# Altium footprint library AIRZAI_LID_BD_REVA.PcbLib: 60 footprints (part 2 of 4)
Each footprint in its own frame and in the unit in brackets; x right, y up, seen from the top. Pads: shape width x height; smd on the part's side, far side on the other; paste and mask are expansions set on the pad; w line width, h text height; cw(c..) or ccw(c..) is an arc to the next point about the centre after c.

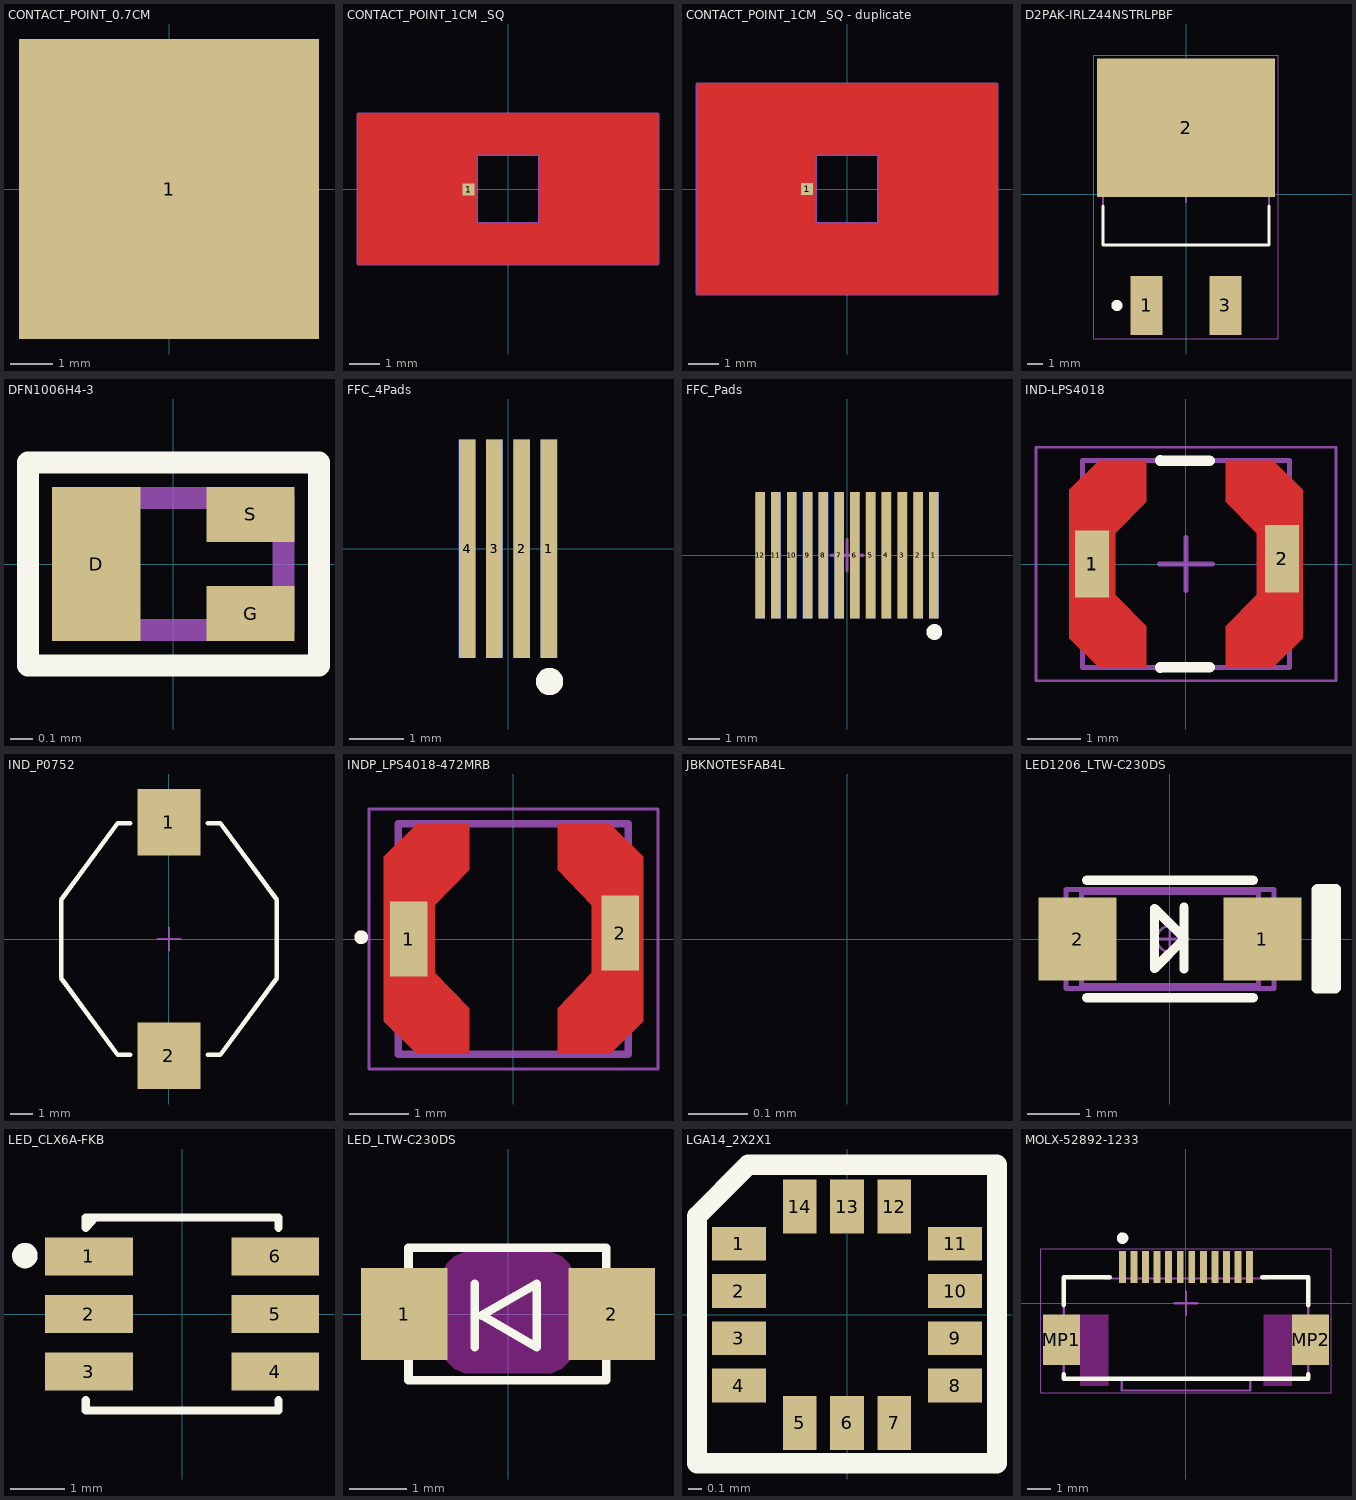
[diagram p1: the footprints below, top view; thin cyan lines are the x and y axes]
## CONTACT_POINT_0.7CM [mm]
pads (1):
  rect 7x7 smd paste-3.5 mask-3.5: 1(0,0)

## CONTACT_POINT_1CM _SQ [mm]
pads (1):
  rect 0.4x0.4 smd paste-2 mask-2: 1(-1.312,-0.018)
Top Layer:
  region: 2.48,-2.5 1.05,-1.15 -1.05,-1.15 -1.05,2.5 -5,2.5 -5,-2.5
  region: -2.48,2.5 -1.05,1.15 1.05,1.15 1.05,-2.5 5,-2.5 5,2.5
Mechanical 1:
  lines w0.1: -5,-2.5 -5,2.5 5,2.5 5,-2.5 -5,-2.5 ; -1.05,-1.15 1.05,-1.15 1.05,1.15 -1.05,1.15 -1.05,-1.15

## CONTACT_POINT_1CM _SQ - duplicate [mm]
pads (1):
  rect 0.4x0.4 smd paste-2 mask-2: 1(-1.325,0)
Top Layer:
  region: 5,-3.5 5,3.5 -3.4,3.5 -1.05,1.15 1.05,1.15 1.05,-3.498 1.052,-3.5
  region: -5,3.5 -5,-3.5 3.4,-3.5 1.05,-1.15 -1.05,-1.15 -1.05,3.498 -1.052,3.5
Mechanical 1:
  lines w0.1: -5,-3.5 -5,3.5 5,3.5 5,-3.5 -5,-3.5 ; -1.05,-1.15 1.05,-1.15 1.05,1.15 -1.05,1.15 -1.05,-1.15

## D2PAK-IRLZ44NSTRLPBF [mm]
pads (3):
  rect 2.08x3.81 smd: 1(-2.54,-7.14) 3(2.54,-7.14)
  rect 11.43x8.89 smd: 2(0,4.29)
Top Overlay:
  circle w0.356: c-4.445,-7.14 r0.178
  lines w0.198: -5.34,-0.74 -5.34,-3.24 5.34,-3.24 5.34,-0.74
Mechanical 4:
  lines w0.127: -5.34,-3.24 -5.34,6.42 ; -5.34,-3.24 5.34,-3.24 ; -5.34,-3.24 -5.34,6.42 ; -5.34,-3.24 5.34,-3.24 ; -5.34,6.42 5.34,6.42 ; -5.34,6.42 5.34,6.42 ; 5.34,-3.24 5.34,6.42 ; 5.34,-3.24 5.34,6.42
Mechanical 15:
  lines w0.1: -0.5,0 0.5,0 ; 0,-0.5 0,0.5
Mechanical 16:
  lines w0.05: -5.95,-9.3 -5.95,8.95 5.95,8.95 5.95,-9.3 -5.95,-9.3
3D body "User Library-D²PAK TO-263-3.STEP": height 4.87, standoff 0, extent -5.054,-7.954 5.106,6.276

## DFN1006H4-3 [mm]
height 5.1
pads (3):
  rect 0.4x0.7 smd paste-0.05 mask+0.05: D(-0.35,0)
  rect 0.4x0.25 smd paste-0.05 mask+0.05: G(0.35,-0.225) S(0.35,0.225)
Top Overlay:
  lines w0.1: -0.66,-0.46 -0.66,0.46 0.66,0.46 0.66,-0.46 -0.66,-0.46
Mechanical 1:
  lines w0.1: -0.5,-0.3 -0.5,0.3 0.5,0.3 0.5,-0.3 -0.5,-0.3
3D body: height 0.5, standoff 0, extent -0.5,-0.3 0.5,0.3

## FFC_4Pads [mm] "(0.50mm"
height 2.052
pads (8):
  rect 0.3x4 smd far side: 1(0.75,0) 2(0.25,0) 3(-0.25,0) 4(-0.75,0)
  rect 0.3x4 smd: 1(0.75,0) 2(0.25,0) 3(-0.25,0) 4(-0.75,0)
Top Overlay:
  circle w0.25: c0.762,-2.432 r0.125

## FFC_Pads [mm] "(0.50mm"
height 2.052
pads (24):
  rect 0.3x4 smd far side: 1(2.75,0) 2(2.25,0) 3(1.75,0) 4(1.25,0) 5(0.75,0) 6(0.25,0) 7(-0.25,0) 8(-0.75,0) 9(-1.25,0) 10(-1.75,0) 11(-2.25,0) 12(-2.75,0)
  rect 0.3x4 smd: 1(2.75,0) 2(2.25,0) 3(1.75,0) 4(1.25,0) 5(0.75,0) 6(0.25,0) 7(-0.25,0) 8(-0.75,0) 9(-1.25,0) 10(-1.75,0) 11(-2.25,0) 12(-2.75,0)
Top Overlay:
  circle w0.25: c2.762,-2.432 r0.125
Mechanical 15:
  lines w0.1: -0.5,0 0.5,0 ; 0,-0.5 0,0.5

## IND-LPS4018 [mm] "Inductor, 2-Leads, Body 3.90x3.90mm, IPC Medium Density"
height 1.8
pads (4):
  rect 0.635x1.27 smd: 1(-1.77,0) 1(-1.77,0) 2(1.81,0.1) 2(1.81,0.1)
Top Layer:
  region: -1.64,-1.945 -0.75,-1.945 -0.75,-1.17 -1.33,-0.575 -1.33,0.575 -0.75,1.17 -0.75,1.945 -1.64,1.945 -2.2,1.395 -2.2,-1.395
  region: 1.64,1.945 0.75,1.945 0.75,1.17 1.33,0.575 1.33,-0.575 0.75,-1.17 0.75,-1.945 1.64,-1.945 2.2,-1.395 2.2,1.395
Top Overlay:
  lines w0.2: -0.487,-1.95 0.443,-1.947 ; -0.487,1.95 0.443,1.947
Top Paste:
  region: -1.64,-1.945 -0.75,-1.945 -0.75,-1.17 -1.33,-0.575 -1.33,0.575 -0.75,1.17 -0.75,1.945 -1.64,1.945 -2.2,1.395 -2.2,-1.395
  region: 1.64,1.945 0.75,1.945 0.75,1.17 1.33,0.575 1.33,-0.575 0.75,-1.17 0.75,-1.945 1.64,-1.945 2.2,-1.395 2.2,1.395
Top Solder:
  region: -1.72,2.09 -0.65,2.09 -0.65,1.16 -1.22,0.53 -1.22,-0.53 -0.65,-1.15 -0.65,-2.09 -1.72,-2.09 -2.34,-1.47 -2.34,1.47
  region: 1.72,-2.09 0.65,-2.09 0.65,-1.1 1.22,-0.53 1.22,0.53 0.65,1.12 0.65,2.09 1.72,2.09 2.34,1.47 2.34,-1.47
Mechanical 13:
  lines w0.1: -1.95,-1.95 -1.95,1.95 1.95,1.95 1.95,-1.95 -1.95,-1.95
Mechanical 15:
  lines w0.05: -2.825,-2.2 -2.825,2.2 2.825,2.2 2.825,-2.2 -2.825,-2.2
  lines w0.1: -0.5,0 0.5,0 ; 0,-0.5 0,0.5
3D body "Coilcraft-LPS4018.STEP": height 1.8, standoff 0, extent -1.99,-1.99 1.99,1.99

## IND_P0752 [mm]
height 5.46
pads (2):
  rect 2.79x2.92 smd paste-0.1 mask+0.1: 1(0,5.145) 2(0,-5.145)
Top Overlay:
  lines w0.2: -4.75,-1.71 -4.75,1.71 ; -1.7,-5.106 -2.261,-5.106 -4.75,-1.71 -4.75,1.71 ; -1.7,5.106 -2.261,5.105 -4.75,1.71 ; 1.7,-5.106 2.261,-5.106 4.75,-1.71 4.75,1.71 ; 1.7,5.106 2.261,5.105 4.75,1.71 ; 4.75,-1.71 4.75,1.71
Mechanical 15:
  lines w0.1: -0.5,0 0.5,0 ; 0,-0.5 0,0.5
3D body: height 5.46, standoff 4.5, extent -4.2,-4.2 4.2,4.2
3D body "User Library-P0752.STEP": height 4.8, standoff 0.05, extent -4.625,-6.3 4.625,6.3

## INDP_LPS4018-472MRB [mm]
pads (2):
  rect 0.635x1.27 smd: 1(-1.77,0) 2(1.81,0.1)
Top Layer:
  region: 1.64,1.945 0.75,1.945 0.75,1.17 1.33,0.575 1.33,-0.575 0.75,-1.17 0.75,-1.945 1.64,-1.945 2.2,-1.395 2.2,1.395
  region: -1.64,-1.945 -0.75,-1.945 -0.75,-1.17 -1.33,-0.575 -1.33,0.575 -0.75,1.17 -0.75,1.945 -1.64,1.945 -2.2,1.395 -2.2,-1.395
Top Overlay:
  circle w0.127: c-2.58,0.03 r0.054
Top Paste:
  region: 1.64,1.945 0.75,1.945 0.75,1.17 1.33,0.575 1.33,-0.575 0.75,-1.17 0.75,-1.945 1.64,-1.945 2.2,-1.395 2.2,1.395
  region: -1.64,-1.945 -0.75,-1.945 -0.75,-1.17 -1.33,-0.575 -1.33,0.575 -0.75,1.17 -0.75,1.945 -1.64,1.945 -2.2,1.395 -2.2,-1.395
Top Solder:
  region: 1.72,-2.09 0.65,-2.09 0.65,-1.1 1.22,-0.53 1.22,0.53 0.65,1.12 0.65,2.09 1.72,2.09 2.34,1.47 2.34,-1.47
  region: -1.72,2.09 -0.65,2.09 -0.65,1.16 -1.22,0.53 -1.22,-0.53 -0.65,-1.15 -0.65,-2.09 -1.72,-2.09 -2.34,-1.47 -2.34,1.47
Mechanical 4:
  lines w0.127: -1.95,-1.95 -1.95,1.95 ; -1.95,-1.95 1.95,-1.95 ; -1.95,-1.95 -1.95,1.95 ; -1.95,-1.95 1.95,-1.95 ; -1.95,1.95 1.95,1.95 ; -1.95,1.95 1.95,1.95 ; 1.95,-1.95 1.95,1.95 ; 1.95,-1.95 1.95,1.95
Mechanical 16:
  lines w0.05: -2.45,-2.2 2.45,-2.2 2.45,2.2 -2.45,2.2 -2.45,-2.2

## JBKNOTESFAB4L [mm]
height 0.33
pads (1):
  round 0 all layers, no hole: 1(0,0)
Drill Drawing:
  text "7.  BOARD FINISH ENIG." at -0.135,-40.976 h1.91
  text "9.  ELECTRICAL TEST REQUIRED, ELECTRICAL TEST MARK," at -0.007,-53.277 h1.91
  text "6.  WARP NOT TO EXCEED IPC SPECIFICATION FOR CLASS 2 PCB'S." at -0.385,-37.055 h1.91
  text "AFFIXED AND LOCATED AS SHOWN, ON BOTTOM TRACE LAYER." at -1.341,-64.282 h1.91
  text "10.  VENDOR IDENTIFICATION, UL COMPLIANCE AND DATE CODE TO BE PERMANTLY" at -1.334,-60.758 h1.91
  text "5.  REFERENCE POINT 0,0 FOR DRILL FILE LISTING." at -0.285,-33.095 h1.91
  text "11.  WARNING: THE MANUFACTURING PROCESSES AND THE MATERIALS ASSOCIATED" at -1,-68.75 h1.91
  text "FINISHED COPPER THICKNESS PER LAYER STACK." at 7.358,-18.546 h1.91
  text "3.  SOLDERMASK BOTH SIDES. THICKNESS NOT TO EXCEED .002 IN." at -0.285,-22.145 h1.91
  text "WITH THIS PART MAY REQUIRE SPECIAL SAFETY PRECAUTIONS." at 8,-72.5 h1.91
  text "1.  BOARD TO BE FABRICATED IN ACCORDANCE WITH IPC-A-600," at -0.535,-7.87 h1.91
  text "NOTES UNLESS OTHERWISE SPECIFIED:" at 0,-3.175 h2.38
  text "2.  MATERIAL: USE AN APPROVED LEAD-FREE FR-4, WITH A MINIMUM 170 TG RATING." at -0.285,-14.833 h1.91
  text "4.  ALL MATERIALS TO HAVE A FLAMMABILITY RATING 94 V-0 OR BETTER," at -0.135,-26.072 h1.91
  text "USING ARTWORK AND DRILL FILES SUPPLIED WITH THIS DRAWING." at 7.557,-11.167 h1.91
  text "LOCATED AS SHOWN, ON BOTTOM TRACE LAYER." at 8.05,-56.34 h1.91
  text "AND BE RoHS COMPLIANT." at 7.757,-29.069 h1.91
  text "8. NO SILKSCREEN." at 0.075,-45.575 h2.1

## LED1206_LTW-C230DS [mm] "Chip Capacitor, Body 3.2x1.6mm, IPC High Density"
height 1.1
pads (2):
  rect 1.5x1.6 smd paste-0.1 mask+0.07: 1(1.775,0) 2(-1.775,0)
Top Overlay:
  lines w0.178: -1.6,-1.13 1.6,-1.13 ; -1.6,1.13 1.6,1.13 ; 0.272,-0.578 0.272,0.003 ; 0.272,0.613 0.272,0.018 ; 0.272,0.003 -0.298,-0.567 -0.298,0.587 0.272,0.018 ; 0.272,0.003 0.272,0.018
  lines w0.198: 2.825,0.947 2.825,-0.953 3.18,-0.953 ; 2.838,0.96 3.193,0.96 3.193,-0.94 ; 3.005,-0.95 3.005,0.95
Mechanical 13:
  lines w0.1: -1.7,-0.9 -1.7,0.9 1.7,0.9 1.7,-0.9 -1.7,-0.9
Mechanical 15:
  circle w0.05: c0,0 r0.25
  lines w0.05: -0.35,0 0.35,0 ; 0,-0.35 0,0.35
  lines w0.1: -2,-0.95 -2,0.95 2,0.95 2,-0.95 -2,-0.95
3D body "User Library-LTST-C230KGKT.STEP": height 0.31, standoff -0.8, extent -1.63,-0.8 1.63,0.8

## LED_CLX6A-FKB [mm] "CREE LED 3 IN 1"
height 2.9
pads (6):
  rect 1.6x0.7 smd paste-0.1 mask+0.07: 1(-1.7,1.05) 2(-1.7,0) 3(-1.7,-1.05) 4(1.7,-1.05) 5(1.7,0) 6(1.7,1.05)
Top Overlay:
  circle w0.25: c-2.87,1.067 r0.108
  lines w0.15: -1.76,-1.575 -1.76,-1.76 1.76,-1.76 1.76,-1.575 ; -1.76,1.575 -1.76,1.76 1.76,1.76 1.76,1.575 ; -1.743,1.59 -1.6,1.75
3D body: height 2.89, standoff 0, extent -1.75,-1.75 1.75,1.75
3D body: height 1.7, standoff 0, extent -1.8,-0.3 1.8,0.3
3D body: height 1.7, standoff 0, extent -1.8,0.75 1.8,1.35
3D body: height 1.7, standoff 0, extent -1.8,-1.325 1.8,-0.725
3D body: height 2.9, standoff 0, extent -1.76,1.49 -1.49,1.76

## LED_LTW-C230DS [mm] "REVERSE MOUNT CHIP LED"
height 1.1
pads (2):
  rect 1.5x1.6 smd paste-0.1 mask+0.07: 1(-1.8,0) 2(1.8,0)
Top Overlay:
  lines w0.15: -0.575,-0.575 -0.575,0.525 ; -1.725,-1.15 -1.725,1.15 1.7,1.15 1.7,-1.15 -1.725,-1.15 ; -0.453,-0.025 0.5,0.525 0.5,-0.575 -0.453,-0.025
Keep-Out Layer:
  board cut-out: -0.65,-1.025 -0.749,-1.025 -0.933,-0.949 -1.074,-0.808 -1.15,-0.624 -1.15,-0.525 -1.15,0.575 -1.15,0.674 -1.074,0.858 -0.933,0.999 -0.749,1.075 -0.65,1.075 0.65,1.075 0.749,1.075 0.933,0.999 1.074,0.858 1.15,0.674 1.15,0.575 1.15,-0.525 1.15,-0.624 1.074,-0.808 0.933,-0.949 0.749,-1.025 0.65,-1.025
3D body: height 0, standoff -1.1, extent -0.675,-0.8 0.825,0.8
3D body: height 0.28, standoff 0, extent -1.6,-0.8 1.6,0.8

## LGA14_2X2X1 [mm]
height 1
pads (14):
  rect 0.4x0.25 smd paste+0 mask+0: 1(-0.8,0.525) 2(-0.8,0.175) 3(-0.8,-0.175) 4(-0.8,-0.525) 8(0.8,-0.525) 9(0.8,-0.175) 10(0.8,0.175) 11(0.8,0.525)
  rect 0.25x0.4 smd paste+0 mask+0: 5(-0.35,-0.8) 6(0,-0.8) 7(0.35,-0.8) 12(0.35,0.8) 13(0,0.8) 14(-0.35,0.8)
Top Overlay:
  lines w0.15: -1.11,-1.1 1.11,-1.1 1.11,1.11 -0.73,1.11 -1.11,0.73 -1.11,-1.1
3D body: height 1, standoff 0, extent -1,-1 1,1

## MOLX-52892-1233 [mm] "FPC Connector, 12-Leads, Right Angle, Pitch 0.5 mm, Mated Height 2.0 mm, SMT"
height 2.052
pads (14):
  rect 0.3x1.4 smd: 1(-2.75,1.575) 2(-2.25,1.575) 3(-1.75,1.575) 4(-1.25,1.575) 5(-0.75,1.575) 6(-0.25,1.575) 7(0.25,1.575) 8(0.75,1.575) 9(1.25,1.575) 10(1.75,1.575) 11(2.25,1.575) 12(2.75,1.575)
  rect 1.6x2.2 smd: MP1(-5.4,-1.575) MP2(5.4,-1.575)
Top Overlay:
  circle w0.25: c-2.75,2.825 r0.125
  lines w0.2: -5.3,-3.075 -5.3,-3.275 5.3,-3.275 5.3,-3.075 ; -5.3,-0.075 -5.3,1.125 -3.3,1.125 ; 3.3,1.125 5.3,1.125 5.3,-0.075
Keep-Out Layer:
  rectangle: -4.6,-3.575 -3.35,-0.475
  rectangle: 3.35,-3.575 4.6,-0.475
Mechanical 13:
  lines w0.1: -5.3,-3.275 -2.785,-3.275 -2.785,-3.775 2.785,-3.775 2.785,-3.275 5.3,-3.275 5.3,1.125 3.5,1.125 3.5,1.075 -3.5,1.075 -3.5,1.125 -5.3,1.125 -5.3,-3.275
Mechanical 15:
  lines w0.05: -6.3,-3.875 -6.3,2.375 6.3,2.375 6.3,-3.875 -6.3,-3.875
  lines w0.1: -0.5,0 0.5,0 ; 0,-0.5 0,0.5
3D body "528921233.stp": height 2.05, standoff 0.01, extent -5.7,-3.775 5.7,1.725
